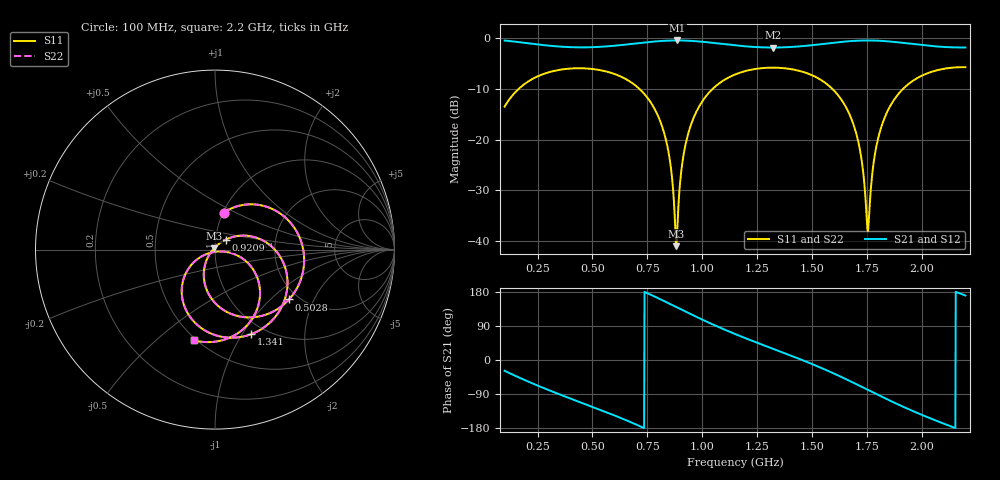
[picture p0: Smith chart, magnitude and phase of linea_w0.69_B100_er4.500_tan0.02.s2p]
! Chirptenna · simulación 3D de una microstrip de dos puertos (S12 = S21, S22 = S11 por simetría)
# HZ S RI R 50
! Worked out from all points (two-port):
!   1101 points, 100 MHz to 2.2 GHz, reference 50 ohm
!   highest |S21| = -0.43 dB at 886.5 MHz (marker M1); lowest = -1.8 dB at 1.322 GHz (marker M2)
!   |S21| within 3 dB of the highest: start of sweep to end of sweep
!   lowest |S11| = -41.0 dB at 882.7 MHz (marker M3), VSWR 1.02, Z = 49.4 + j0.633 ohm
!   |S11| at or under -10 dB: start of sweep to 163.6 MHz; 714.8 MHz to 1.048 GHz (332.8 MHz wide, 37.8 % of centre); 1.594 GHz to 1.915 GHz (321.2 MHz wide, 18.3 % of centre)
!   |S22| runs from -41.0 to -5.7 dB; largest |S21 - S12| = 0
!   S11 on the Smith chart (normalised r, x): 100 MHz: 1.01, +0.44; 502.8 MHz: 1.78, -1.31; 920.9 MHz: 1.12, +0.13; 1.341 GHz: 0.86, -1.10; 2.2 GHz: 0.49, -0.67
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1e8  0.0499 0.2061  0.834 -0.4533  0.834 -0.4533  0.0499 0.2061
2.584545e8  0.388 0.1822  0.3031 -0.8104  0.3031 -0.8104  0.388 0.1822
4.512727e8  0.4694 -0.1893  -0.3169 -0.7492  -0.3169 -0.7492  0.4694 -0.1893
5.028182e8  0.4125 -0.2774  -0.4595 -0.6757  -0.4595 -0.6757  0.4125 -0.2774
6.517273e8  0.1366 -0.3724  -0.8055 -0.3186  -0.8055 -0.3186  0.1366 -0.3724
8.006364e8  -0.0619 -0.1573  -0.8939 0.2766  -0.8939 0.2766  -0.0619 -0.1573
8.483636e8  -0.046 -0.0564  -0.8164 0.4823  -0.8164 0.4823  -0.046 -0.0564
8.827273e8  -0.00624 0.0064  -0.7251 0.6159  -0.7251 0.6159  -0.00624 0.0064
8.865455e8  -0.000531 0.0125  -0.7133 0.6296  -0.7133 0.6296  -0.000531 0.0125
9.209091e8  0.06 0.056  -0.5942 0.7394  -0.5942 0.7394  0.06 0.056
1.003e9  0.2337 0.0653  -0.2535 0.8873  -0.2535 0.8873  0.2337 0.0653
1.15e9  0.4037 -0.1734  0.3103 0.7925  0.3103 0.7925  0.4037 -0.1734
1.321818e9  0.2364 -0.4557  0.7029 0.4038  0.7029 0.4038  0.2364 -0.4557
1.340909e9  0.2019 -0.4711  0.731 0.3516  0.731 0.3516  0.2019 -0.4711
1.501273e9  -0.0976 -0.4207  0.8396 -0.159  0.8396 -0.159  -0.0976 -0.4207
1.680727e9  -0.1341 -0.0876  0.5049 -0.7915  0.5049 -0.7915  -0.1341 -0.0876
1.722727e9  -0.0646 -0.0326  0.3343 -0.888  0.3343 -0.888  -0.0646 -0.0326
1.755182e9  0.0014 -0.0124  0.1869 -0.9327  0.1869 -0.9327  0.0014 -0.0124
1.793364e9  0.0824 -0.0171  0.00656 -0.9477  0.00656 -0.9477  0.0824 -0.0171
1.850636e9  0.1863 -0.078  -0.2523 -0.896  -0.2523 -0.896  0.1863 -0.078
2.011e9  0.2081 -0.3844  -0.7162 -0.4633  -0.7162 -0.4633  0.2081 -0.3844
2.2e9  -0.1157 -0.5057  -0.7995 0.139  -0.7995 0.139  -0.1157 -0.5057
